VERSION 5.7 ;
  NOWIREEXTENSIONATPIN ON ;
  DIVIDERCHAR "/" ;
  BUSBITCHARS "[]" ;
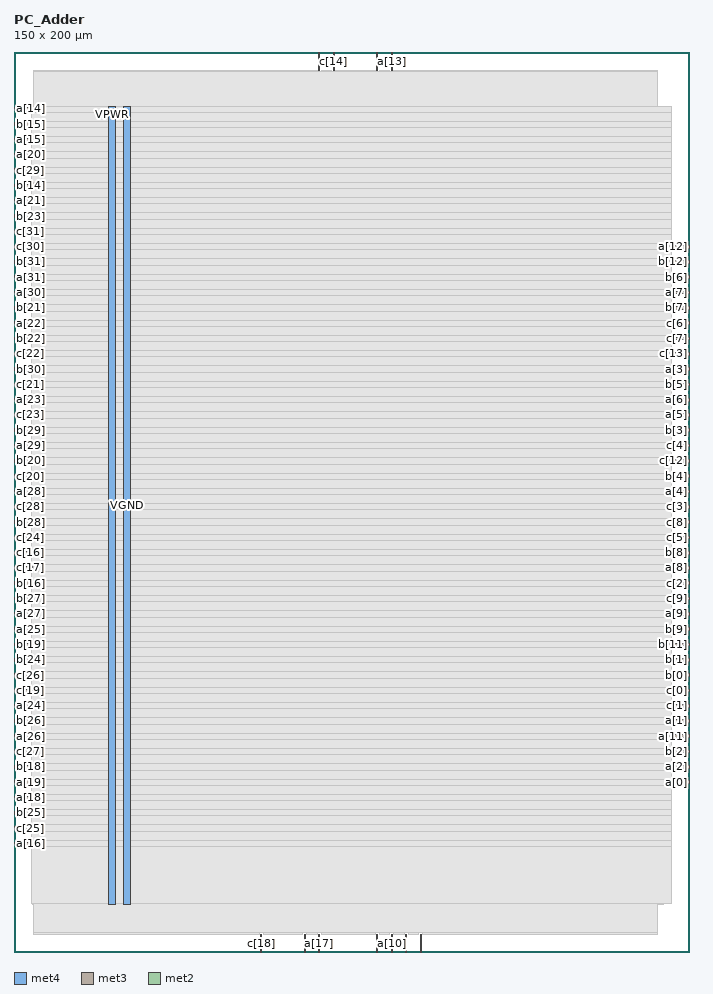
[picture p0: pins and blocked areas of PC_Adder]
MACRO PC_Adder
  CLASS BLOCK ;
  FOREIGN PC_Adder ;
  ORIGIN 0.000 0.000 ;
  SIZE 150.000 BY 200.000 ;
  PIN VGND
    DIRECTION INOUT ;
    USE GROUND ;
    PORT
      LAYER met4 ;
        RECT 24.340 10.640 25.940 187.920 ;
    END
  END VGND
  PIN VPWR
    DIRECTION INOUT ;
    USE POWER ;
    PORT
      LAYER met4 ;
        RECT 21.040 10.640 22.640 187.920 ;
    END
  END VPWR
  PIN a[0]
    DIRECTION INPUT ;
    USE SIGNAL ;
    ANTENNAGATEAREA 0.196500 ;
    PORT
      LAYER met3 ;
        RECT 146.000 37.440 150.000 38.040 ;
    END
  END a[0]
  PIN a[10]
    DIRECTION INPUT ;
    USE SIGNAL ;
    ANTENNAGATEAREA 0.196500 ;
    PORT
      LAYER met2 ;
        RECT 83.810 0.000 84.090 4.000 ;
    END
  END a[10]
  PIN a[11]
    DIRECTION INPUT ;
    USE SIGNAL ;
    ANTENNAGATEAREA 0.196500 ;
    PORT
      LAYER met3 ;
        RECT 146.000 47.640 150.000 48.240 ;
    END
  END a[11]
  PIN a[12]
    DIRECTION INPUT ;
    USE SIGNAL ;
    ANTENNAGATEAREA 0.196500 ;
    PORT
      LAYER met3 ;
        RECT 146.000 156.440 150.000 157.040 ;
    END
  END a[12]
  PIN a[13]
    DIRECTION INPUT ;
    USE SIGNAL ;
    ANTENNAGATEAREA 0.196500 ;
    PORT
      LAYER met2 ;
        RECT 83.810 196.000 84.090 200.000 ;
    END
  END a[13]
  PIN a[14]
    DIRECTION INPUT ;
    USE SIGNAL ;
    ANTENNAGATEAREA 0.196500 ;
    PORT
      LAYER met3 ;
        RECT 0.000 187.040 4.000 187.640 ;
    END
  END a[14]
  PIN a[15]
    DIRECTION INPUT ;
    USE SIGNAL ;
    ANTENNAGATEAREA 0.196500 ;
    PORT
      LAYER met3 ;
        RECT 0.000 180.240 4.000 180.840 ;
    END
  END a[15]
  PIN a[16]
    DIRECTION INPUT ;
    USE SIGNAL ;
    ANTENNAGATEAREA 0.196500 ;
    PORT
      LAYER met3 ;
        RECT 0.000 23.840 4.000 24.440 ;
    END
  END a[16]
  PIN a[17]
    DIRECTION INPUT ;
    USE SIGNAL ;
    ANTENNAGATEAREA 0.196500 ;
    PORT
      LAYER met2 ;
        RECT 67.710 0.000 67.990 4.000 ;
    END
  END a[17]
  PIN a[18]
    DIRECTION INPUT ;
    USE SIGNAL ;
    ANTENNAGATEAREA 0.196500 ;
    PORT
      LAYER met3 ;
        RECT 0.000 34.040 4.000 34.640 ;
    END
  END a[18]
  PIN a[19]
    DIRECTION INPUT ;
    USE SIGNAL ;
    ANTENNAGATEAREA 0.196500 ;
    PORT
      LAYER met3 ;
        RECT 0.000 37.440 4.000 38.040 ;
    END
  END a[19]
  PIN a[1]
    DIRECTION INPUT ;
    USE SIGNAL ;
    ANTENNAGATEAREA 0.196500 ;
    PORT
      LAYER met3 ;
        RECT 146.000 51.040 150.000 51.640 ;
    END
  END a[1]
  PIN a[20]
    DIRECTION INPUT ;
    USE SIGNAL ;
    ANTENNAGATEAREA 0.196500 ;
    PORT
      LAYER met3 ;
        RECT 0.000 176.840 4.000 177.440 ;
    END
  END a[20]
  PIN a[21]
    DIRECTION INPUT ;
    USE SIGNAL ;
    ANTENNAGATEAREA 0.196500 ;
    PORT
      LAYER met3 ;
        RECT 0.000 166.640 4.000 167.240 ;
    END
  END a[21]
  PIN a[22]
    DIRECTION INPUT ;
    USE SIGNAL ;
    ANTENNAGATEAREA 0.196500 ;
    PORT
      LAYER met3 ;
        RECT 0.000 139.440 4.000 140.040 ;
    END
  END a[22]
  PIN a[23]
    DIRECTION INPUT ;
    USE SIGNAL ;
    ANTENNAGATEAREA 0.196500 ;
    PORT
      LAYER met3 ;
        RECT 0.000 122.440 4.000 123.040 ;
    END
  END a[23]
  PIN a[24]
    DIRECTION INPUT ;
    USE SIGNAL ;
    ANTENNAGATEAREA 0.196500 ;
    PORT
      LAYER met3 ;
        RECT 0.000 54.440 4.000 55.040 ;
    END
  END a[24]
  PIN a[25]
    DIRECTION INPUT ;
    USE SIGNAL ;
    ANTENNAGATEAREA 0.196500 ;
    PORT
      LAYER met3 ;
        RECT 0.000 71.440 4.000 72.040 ;
    END
  END a[25]
  PIN a[26]
    DIRECTION INPUT ;
    USE SIGNAL ;
    ANTENNAGATEAREA 0.196500 ;
    PORT
      LAYER met3 ;
        RECT 0.000 47.640 4.000 48.240 ;
    END
  END a[26]
  PIN a[27]
    DIRECTION INPUT ;
    USE SIGNAL ;
    ANTENNAGATEAREA 0.196500 ;
    PORT
      LAYER met3 ;
        RECT 0.000 74.840 4.000 75.440 ;
    END
  END a[27]
  PIN a[28]
    DIRECTION INPUT ;
    USE SIGNAL ;
    ANTENNAGATEAREA 0.196500 ;
    PORT
      LAYER met3 ;
        RECT 0.000 102.040 4.000 102.640 ;
    END
  END a[28]
  PIN a[29]
    DIRECTION INPUT ;
    USE SIGNAL ;
    ANTENNAGATEAREA 0.196500 ;
    PORT
      LAYER met3 ;
        RECT 0.000 112.240 4.000 112.840 ;
    END
  END a[29]
  PIN a[2]
    DIRECTION INPUT ;
    USE SIGNAL ;
    ANTENNAGATEAREA 0.196500 ;
    PORT
      LAYER met3 ;
        RECT 146.000 40.840 150.000 41.440 ;
    END
  END a[2]
  PIN a[30]
    DIRECTION INPUT ;
    USE SIGNAL ;
    ANTENNAGATEAREA 0.196500 ;
    PORT
      LAYER met3 ;
        RECT 0.000 146.240 4.000 146.840 ;
    END
  END a[30]
  PIN a[31]
    DIRECTION INPUT ;
    USE SIGNAL ;
    ANTENNAGATEAREA 0.196500 ;
    PORT
      LAYER met3 ;
        RECT 0.000 149.640 4.000 150.240 ;
    END
  END a[31]
  PIN a[3]
    DIRECTION INPUT ;
    USE SIGNAL ;
    ANTENNAGATEAREA 0.196500 ;
    PORT
      LAYER met3 ;
        RECT 146.000 129.240 150.000 129.840 ;
    END
  END a[3]
  PIN a[4]
    DIRECTION INPUT ;
    USE SIGNAL ;
    ANTENNAGATEAREA 0.196500 ;
    PORT
      LAYER met3 ;
        RECT 146.000 102.040 150.000 102.640 ;
    END
  END a[4]
  PIN a[5]
    DIRECTION INPUT ;
    USE SIGNAL ;
    ANTENNAGATEAREA 0.196500 ;
    PORT
      LAYER met3 ;
        RECT 146.000 119.040 150.000 119.640 ;
    END
  END a[5]
  PIN a[6]
    DIRECTION INPUT ;
    USE SIGNAL ;
    ANTENNAGATEAREA 0.196500 ;
    PORT
      LAYER met3 ;
        RECT 146.000 122.440 150.000 123.040 ;
    END
  END a[6]
  PIN a[7]
    DIRECTION INPUT ;
    USE SIGNAL ;
    ANTENNAGATEAREA 0.196500 ;
    PORT
      LAYER met3 ;
        RECT 146.000 146.240 150.000 146.840 ;
    END
  END a[7]
  PIN a[8]
    DIRECTION INPUT ;
    USE SIGNAL ;
    ANTENNAGATEAREA 0.196500 ;
    PORT
      LAYER met3 ;
        RECT 146.000 85.040 150.000 85.640 ;
    END
  END a[8]
  PIN a[9]
    DIRECTION INPUT ;
    USE SIGNAL ;
    ANTENNAGATEAREA 0.196500 ;
    PORT
      LAYER met3 ;
        RECT 146.000 74.840 150.000 75.440 ;
    END
  END a[9]
  PIN b[0]
    DIRECTION INPUT ;
    USE SIGNAL ;
    ANTENNAGATEAREA 0.196500 ;
    PORT
      LAYER met3 ;
        RECT 146.000 61.240 150.000 61.840 ;
    END
  END b[0]
  PIN b[10]
    DIRECTION INPUT ;
    USE SIGNAL ;
    ANTENNAGATEAREA 0.196500 ;
    PORT
      LAYER met2 ;
        RECT 80.590 0.000 80.870 4.000 ;
    END
  END b[10]
  PIN b[11]
    DIRECTION INPUT ;
    USE SIGNAL ;
    ANTENNAGATEAREA 0.196500 ;
    PORT
      LAYER met3 ;
        RECT 146.000 68.040 150.000 68.640 ;
    END
  END b[11]
  PIN b[12]
    DIRECTION INPUT ;
    USE SIGNAL ;
    ANTENNAGATEAREA 0.196500 ;
    PORT
      LAYER met3 ;
        RECT 146.000 153.040 150.000 153.640 ;
    END
  END b[12]
  PIN b[13]
    DIRECTION INPUT ;
    USE SIGNAL ;
    ANTENNAGATEAREA 0.196500 ;
    PORT
      LAYER met2 ;
        RECT 80.590 196.000 80.870 200.000 ;
    END
  END b[13]
  PIN b[14]
    DIRECTION INPUT ;
    USE SIGNAL ;
    ANTENNAGATEAREA 0.196500 ;
    PORT
      LAYER met3 ;
        RECT 0.000 170.040 4.000 170.640 ;
    END
  END b[14]
  PIN b[15]
    DIRECTION INPUT ;
    USE SIGNAL ;
    ANTENNAGATEAREA 0.196500 ;
    PORT
      LAYER met3 ;
        RECT 0.000 183.640 4.000 184.240 ;
    END
  END b[15]
  PIN b[16]
    DIRECTION INPUT ;
    USE SIGNAL ;
    ANTENNAGATEAREA 0.196500 ;
    PORT
      LAYER met3 ;
        RECT 0.000 81.640 4.000 82.240 ;
    END
  END b[16]
  PIN b[17]
    DIRECTION INPUT ;
    USE SIGNAL ;
    ANTENNAGATEAREA 0.196500 ;
    PORT
      LAYER met2 ;
        RECT 64.490 0.000 64.770 4.000 ;
    END
  END b[17]
  PIN b[18]
    DIRECTION INPUT ;
    USE SIGNAL ;
    ANTENNAGATEAREA 0.196500 ;
    PORT
      LAYER met3 ;
        RECT 0.000 40.840 4.000 41.440 ;
    END
  END b[18]
  PIN b[19]
    DIRECTION INPUT ;
    USE SIGNAL ;
    ANTENNAGATEAREA 0.196500 ;
    PORT
      LAYER met3 ;
        RECT 0.000 68.040 4.000 68.640 ;
    END
  END b[19]
  PIN b[1]
    DIRECTION INPUT ;
    USE SIGNAL ;
    ANTENNAGATEAREA 0.196500 ;
    PORT
      LAYER met3 ;
        RECT 146.000 64.640 150.000 65.240 ;
    END
  END b[1]
  PIN b[20]
    DIRECTION INPUT ;
    USE SIGNAL ;
    ANTENNAGATEAREA 0.196500 ;
    PORT
      LAYER met3 ;
        RECT 0.000 108.840 4.000 109.440 ;
    END
  END b[20]
  PIN b[21]
    DIRECTION INPUT ;
    USE SIGNAL ;
    ANTENNAGATEAREA 0.196500 ;
    PORT
      LAYER met3 ;
        RECT 0.000 142.840 4.000 143.440 ;
    END
  END b[21]
  PIN b[22]
    DIRECTION INPUT ;
    USE SIGNAL ;
    ANTENNAGATEAREA 0.196500 ;
    PORT
      LAYER met3 ;
        RECT 0.000 136.040 4.000 136.640 ;
    END
  END b[22]
  PIN b[23]
    DIRECTION INPUT ;
    USE SIGNAL ;
    ANTENNAGATEAREA 0.196500 ;
    PORT
      LAYER met3 ;
        RECT 0.000 163.240 4.000 163.840 ;
    END
  END b[23]
  PIN b[24]
    DIRECTION INPUT ;
    USE SIGNAL ;
    ANTENNAGATEAREA 0.196500 ;
    PORT
      LAYER met3 ;
        RECT 0.000 64.640 4.000 65.240 ;
    END
  END b[24]
  PIN b[25]
    DIRECTION INPUT ;
    USE SIGNAL ;
    ANTENNAGATEAREA 0.196500 ;
    PORT
      LAYER met3 ;
        RECT 0.000 30.640 4.000 31.240 ;
    END
  END b[25]
  PIN b[26]
    DIRECTION INPUT ;
    USE SIGNAL ;
    ANTENNAGATEAREA 0.196500 ;
    PORT
      LAYER met3 ;
        RECT 0.000 51.040 4.000 51.640 ;
    END
  END b[26]
  PIN b[27]
    DIRECTION INPUT ;
    USE SIGNAL ;
    ANTENNAGATEAREA 0.196500 ;
    PORT
      LAYER met3 ;
        RECT 0.000 78.240 4.000 78.840 ;
    END
  END b[27]
  PIN b[28]
    DIRECTION INPUT ;
    USE SIGNAL ;
    ANTENNAGATEAREA 0.196500 ;
    PORT
      LAYER met3 ;
        RECT 0.000 95.240 4.000 95.840 ;
    END
  END b[28]
  PIN b[29]
    DIRECTION INPUT ;
    USE SIGNAL ;
    ANTENNAGATEAREA 0.196500 ;
    PORT
      LAYER met3 ;
        RECT 0.000 115.640 4.000 116.240 ;
    END
  END b[29]
  PIN b[2]
    DIRECTION INPUT ;
    USE SIGNAL ;
    ANTENNAGATEAREA 0.196500 ;
    PORT
      LAYER met3 ;
        RECT 146.000 44.240 150.000 44.840 ;
    END
  END b[2]
  PIN b[30]
    DIRECTION INPUT ;
    USE SIGNAL ;
    ANTENNAGATEAREA 0.196500 ;
    PORT
      LAYER met3 ;
        RECT 0.000 129.240 4.000 129.840 ;
    END
  END b[30]
  PIN b[31]
    DIRECTION INPUT ;
    USE SIGNAL ;
    ANTENNAGATEAREA 0.196500 ;
    PORT
      LAYER met3 ;
        RECT 0.000 153.040 4.000 153.640 ;
    END
  END b[31]
  PIN b[3]
    DIRECTION INPUT ;
    USE SIGNAL ;
    ANTENNAGATEAREA 0.196500 ;
    PORT
      LAYER met3 ;
        RECT 146.000 115.640 150.000 116.240 ;
    END
  END b[3]
  PIN b[4]
    DIRECTION INPUT ;
    USE SIGNAL ;
    ANTENNAGATEAREA 0.196500 ;
    PORT
      LAYER met3 ;
        RECT 146.000 105.440 150.000 106.040 ;
    END
  END b[4]
  PIN b[5]
    DIRECTION INPUT ;
    USE SIGNAL ;
    ANTENNAGATEAREA 0.196500 ;
    PORT
      LAYER met3 ;
        RECT 146.000 125.840 150.000 126.440 ;
    END
  END b[5]
  PIN b[6]
    DIRECTION INPUT ;
    USE SIGNAL ;
    ANTENNAGATEAREA 0.196500 ;
    PORT
      LAYER met3 ;
        RECT 146.000 149.640 150.000 150.240 ;
    END
  END b[6]
  PIN b[7]
    DIRECTION INPUT ;
    USE SIGNAL ;
    ANTENNAGATEAREA 0.196500 ;
    PORT
      LAYER met3 ;
        RECT 146.000 142.840 150.000 143.440 ;
    END
  END b[7]
  PIN b[8]
    DIRECTION INPUT ;
    USE SIGNAL ;
    ANTENNAGATEAREA 0.196500 ;
    PORT
      LAYER met3 ;
        RECT 146.000 88.440 150.000 89.040 ;
    END
  END b[8]
  PIN b[9]
    DIRECTION INPUT ;
    USE SIGNAL ;
    ANTENNAGATEAREA 0.196500 ;
    PORT
      LAYER met3 ;
        RECT 146.000 71.440 150.000 72.040 ;
    END
  END b[9]
  PIN c[0]
    DIRECTION OUTPUT ;
    USE SIGNAL ;
    ANTENNADIFFAREA 0.445500 ;
    PORT
      LAYER met3 ;
        RECT 146.000 57.840 150.000 58.440 ;
    END
  END c[0]
  PIN c[10]
    DIRECTION OUTPUT ;
    USE SIGNAL ;
    ANTENNADIFFAREA 0.445500 ;
    PORT
      LAYER met2 ;
        RECT 90.250 0.000 90.530 4.000 ;
    END
  END c[10]
  PIN c[11]
    DIRECTION OUTPUT ;
    USE SIGNAL ;
    ANTENNADIFFAREA 0.445500 ;
    PORT
      LAYER met2 ;
        RECT 87.030 0.000 87.310 4.000 ;
    END
  END c[11]
  PIN c[12]
    DIRECTION OUTPUT ;
    USE SIGNAL ;
    ANTENNADIFFAREA 0.445500 ;
    PORT
      LAYER met3 ;
        RECT 146.000 108.840 150.000 109.440 ;
    END
  END c[12]
  PIN c[13]
    DIRECTION OUTPUT ;
    USE SIGNAL ;
    ANTENNADIFFAREA 0.445500 ;
    PORT
      LAYER met3 ;
        RECT 146.000 132.640 150.000 133.240 ;
    END
  END c[13]
  PIN c[14]
    DIRECTION OUTPUT ;
    USE SIGNAL ;
    ANTENNADIFFAREA 0.795200 ;
    PORT
      LAYER met2 ;
        RECT 70.930 196.000 71.210 200.000 ;
    END
  END c[14]
  PIN c[15]
    DIRECTION OUTPUT ;
    USE SIGNAL ;
    ANTENNADIFFAREA 0.795200 ;
    PORT
      LAYER met2 ;
        RECT 67.710 196.000 67.990 200.000 ;
    END
  END c[15]
  PIN c[16]
    DIRECTION OUTPUT ;
    USE SIGNAL ;
    ANTENNADIFFAREA 0.445500 ;
    PORT
      LAYER met3 ;
        RECT 0.000 88.440 4.000 89.040 ;
    END
  END c[16]
  PIN c[17]
    DIRECTION OUTPUT ;
    USE SIGNAL ;
    ANTENNADIFFAREA 0.445500 ;
    PORT
      LAYER met3 ;
        RECT 0.000 85.040 4.000 85.640 ;
    END
  END c[17]
  PIN c[18]
    DIRECTION OUTPUT ;
    USE SIGNAL ;
    ANTENNADIFFAREA 0.445500 ;
    PORT
      LAYER met2 ;
        RECT 54.830 0.000 55.110 4.000 ;
    END
  END c[18]
  PIN c[19]
    DIRECTION OUTPUT ;
    USE SIGNAL ;
    ANTENNADIFFAREA 0.445500 ;
    PORT
      LAYER met3 ;
        RECT 0.000 57.840 4.000 58.440 ;
    END
  END c[19]
  PIN c[1]
    DIRECTION OUTPUT ;
    USE SIGNAL ;
    ANTENNADIFFAREA 0.445500 ;
    PORT
      LAYER met3 ;
        RECT 146.000 54.440 150.000 55.040 ;
    END
  END c[1]
  PIN c[20]
    DIRECTION OUTPUT ;
    USE SIGNAL ;
    ANTENNADIFFAREA 0.445500 ;
    PORT
      LAYER met3 ;
        RECT 0.000 105.440 4.000 106.040 ;
    END
  END c[20]
  PIN c[21]
    DIRECTION OUTPUT ;
    USE SIGNAL ;
    ANTENNADIFFAREA 0.445500 ;
    PORT
      LAYER met3 ;
        RECT 0.000 125.840 4.000 126.440 ;
    END
  END c[21]
  PIN c[22]
    DIRECTION OUTPUT ;
    USE SIGNAL ;
    ANTENNADIFFAREA 0.445500 ;
    PORT
      LAYER met3 ;
        RECT 0.000 132.640 4.000 133.240 ;
    END
  END c[22]
  PIN c[23]
    DIRECTION OUTPUT ;
    USE SIGNAL ;
    ANTENNADIFFAREA 0.445500 ;
    PORT
      LAYER met3 ;
        RECT 0.000 119.040 4.000 119.640 ;
    END
  END c[23]
  PIN c[24]
    DIRECTION OUTPUT ;
    USE SIGNAL ;
    ANTENNADIFFAREA 0.445500 ;
    PORT
      LAYER met3 ;
        RECT 0.000 91.840 4.000 92.440 ;
    END
  END c[24]
  PIN c[25]
    DIRECTION OUTPUT ;
    USE SIGNAL ;
    ANTENNADIFFAREA 0.445500 ;
    PORT
      LAYER met3 ;
        RECT 0.000 27.240 4.000 27.840 ;
    END
  END c[25]
  PIN c[26]
    DIRECTION OUTPUT ;
    USE SIGNAL ;
    ANTENNADIFFAREA 0.445500 ;
    PORT
      LAYER met3 ;
        RECT 0.000 61.240 4.000 61.840 ;
    END
  END c[26]
  PIN c[27]
    DIRECTION OUTPUT ;
    USE SIGNAL ;
    ANTENNADIFFAREA 0.445500 ;
    PORT
      LAYER met3 ;
        RECT 0.000 44.240 4.000 44.840 ;
    END
  END c[27]
  PIN c[28]
    DIRECTION OUTPUT ;
    USE SIGNAL ;
    ANTENNADIFFAREA 0.445500 ;
    PORT
      LAYER met3 ;
        RECT 0.000 98.640 4.000 99.240 ;
    END
  END c[28]
  PIN c[29]
    DIRECTION OUTPUT ;
    USE SIGNAL ;
    ANTENNADIFFAREA 0.445500 ;
    PORT
      LAYER met3 ;
        RECT 0.000 173.440 4.000 174.040 ;
    END
  END c[29]
  PIN c[2]
    DIRECTION OUTPUT ;
    USE SIGNAL ;
    ANTENNADIFFAREA 0.445500 ;
    PORT
      LAYER met3 ;
        RECT 146.000 81.640 150.000 82.240 ;
    END
  END c[2]
  PIN c[30]
    DIRECTION OUTPUT ;
    USE SIGNAL ;
    ANTENNADIFFAREA 0.445500 ;
    PORT
      LAYER met3 ;
        RECT 0.000 156.440 4.000 157.040 ;
    END
  END c[30]
  PIN c[31]
    DIRECTION OUTPUT ;
    USE SIGNAL ;
    ANTENNADIFFAREA 0.445500 ;
    PORT
      LAYER met3 ;
        RECT 0.000 159.840 4.000 160.440 ;
    END
  END c[31]
  PIN c[3]
    DIRECTION OUTPUT ;
    USE SIGNAL ;
    ANTENNADIFFAREA 0.445500 ;
    PORT
      LAYER met3 ;
        RECT 146.000 98.640 150.000 99.240 ;
    END
  END c[3]
  PIN c[4]
    DIRECTION OUTPUT ;
    USE SIGNAL ;
    ANTENNADIFFAREA 0.445500 ;
    PORT
      LAYER met3 ;
        RECT 146.000 112.240 150.000 112.840 ;
    END
  END c[4]
  PIN c[5]
    DIRECTION OUTPUT ;
    USE SIGNAL ;
    ANTENNADIFFAREA 0.445500 ;
    PORT
      LAYER met3 ;
        RECT 146.000 91.840 150.000 92.440 ;
    END
  END c[5]
  PIN c[6]
    DIRECTION OUTPUT ;
    USE SIGNAL ;
    ANTENNADIFFAREA 0.445500 ;
    PORT
      LAYER met3 ;
        RECT 146.000 139.440 150.000 140.040 ;
    END
  END c[6]
  PIN c[7]
    DIRECTION OUTPUT ;
    USE SIGNAL ;
    ANTENNADIFFAREA 0.445500 ;
    PORT
      LAYER met3 ;
        RECT 146.000 136.040 150.000 136.640 ;
    END
  END c[7]
  PIN c[8]
    DIRECTION OUTPUT ;
    USE SIGNAL ;
    ANTENNADIFFAREA 0.445500 ;
    PORT
      LAYER met3 ;
        RECT 146.000 95.240 150.000 95.840 ;
    END
  END c[8]
  PIN c[9]
    DIRECTION OUTPUT ;
    USE SIGNAL ;
    ANTENNADIFFAREA 0.445500 ;
    PORT
      LAYER met3 ;
        RECT 146.000 78.240 150.000 78.840 ;
    END
  END c[9]
  OBS
      LAYER nwell ;
        RECT 5.330 10.795 144.630 187.870 ;
      LAYER li1 ;
        RECT 5.520 10.795 144.440 187.765 ;
      LAYER met1 ;
        RECT 4.210 10.640 144.440 187.920 ;
      LAYER met2 ;
        RECT 4.230 195.720 67.430 196.000 ;
        RECT 68.270 195.720 70.650 196.000 ;
        RECT 71.490 195.720 80.310 196.000 ;
        RECT 81.150 195.720 83.530 196.000 ;
        RECT 84.370 195.720 142.970 196.000 ;
        RECT 4.230 4.280 142.970 195.720 ;
        RECT 4.230 4.000 54.550 4.280 ;
        RECT 55.390 4.000 64.210 4.280 ;
        RECT 65.050 4.000 67.430 4.280 ;
        RECT 68.270 4.000 80.310 4.280 ;
        RECT 81.150 4.000 83.530 4.280 ;
        RECT 84.370 4.000 86.750 4.280 ;
        RECT 87.590 4.000 89.970 4.280 ;
        RECT 90.810 4.000 142.970 4.280 ;
      LAYER met3 ;
        RECT 4.400 186.640 146.000 187.845 ;
        RECT 3.990 184.640 146.000 186.640 ;
        RECT 4.400 183.240 146.000 184.640 ;
        RECT 3.990 181.240 146.000 183.240 ;
        RECT 4.400 179.840 146.000 181.240 ;
        RECT 3.990 177.840 146.000 179.840 ;
        RECT 4.400 176.440 146.000 177.840 ;
        RECT 3.990 174.440 146.000 176.440 ;
        RECT 4.400 173.040 146.000 174.440 ;
        RECT 3.990 171.040 146.000 173.040 ;
        RECT 4.400 169.640 146.000 171.040 ;
        RECT 3.990 167.640 146.000 169.640 ;
        RECT 4.400 166.240 146.000 167.640 ;
        RECT 3.990 164.240 146.000 166.240 ;
        RECT 4.400 162.840 146.000 164.240 ;
        RECT 3.990 160.840 146.000 162.840 ;
        RECT 4.400 159.440 146.000 160.840 ;
        RECT 3.990 157.440 146.000 159.440 ;
        RECT 4.400 156.040 145.600 157.440 ;
        RECT 3.990 154.040 146.000 156.040 ;
        RECT 4.400 152.640 145.600 154.040 ;
        RECT 3.990 150.640 146.000 152.640 ;
        RECT 4.400 149.240 145.600 150.640 ;
        RECT 3.990 147.240 146.000 149.240 ;
        RECT 4.400 145.840 145.600 147.240 ;
        RECT 3.990 143.840 146.000 145.840 ;
        RECT 4.400 142.440 145.600 143.840 ;
        RECT 3.990 140.440 146.000 142.440 ;
        RECT 4.400 139.040 145.600 140.440 ;
        RECT 3.990 137.040 146.000 139.040 ;
        RECT 4.400 135.640 145.600 137.040 ;
        RECT 3.990 133.640 146.000 135.640 ;
        RECT 4.400 132.240 145.600 133.640 ;
        RECT 3.990 130.240 146.000 132.240 ;
        RECT 4.400 128.840 145.600 130.240 ;
        RECT 3.990 126.840 146.000 128.840 ;
        RECT 4.400 125.440 145.600 126.840 ;
        RECT 3.990 123.440 146.000 125.440 ;
        RECT 4.400 122.040 145.600 123.440 ;
        RECT 3.990 120.040 146.000 122.040 ;
        RECT 4.400 118.640 145.600 120.040 ;
        RECT 3.990 116.640 146.000 118.640 ;
        RECT 4.400 115.240 145.600 116.640 ;
        RECT 3.990 113.240 146.000 115.240 ;
        RECT 4.400 111.840 145.600 113.240 ;
        RECT 3.990 109.840 146.000 111.840 ;
        RECT 4.400 108.440 145.600 109.840 ;
        RECT 3.990 106.440 146.000 108.440 ;
        RECT 4.400 105.040 145.600 106.440 ;
        RECT 3.990 103.040 146.000 105.040 ;
        RECT 4.400 101.640 145.600 103.040 ;
        RECT 3.990 99.640 146.000 101.640 ;
        RECT 4.400 98.240 145.600 99.640 ;
        RECT 3.990 96.240 146.000 98.240 ;
        RECT 4.400 94.840 145.600 96.240 ;
        RECT 3.990 92.840 146.000 94.840 ;
        RECT 4.400 91.440 145.600 92.840 ;
        RECT 3.990 89.440 146.000 91.440 ;
        RECT 4.400 88.040 145.600 89.440 ;
        RECT 3.990 86.040 146.000 88.040 ;
        RECT 4.400 84.640 145.600 86.040 ;
        RECT 3.990 82.640 146.000 84.640 ;
        RECT 4.400 81.240 145.600 82.640 ;
        RECT 3.990 79.240 146.000 81.240 ;
        RECT 4.400 77.840 145.600 79.240 ;
        RECT 3.990 75.840 146.000 77.840 ;
        RECT 4.400 74.440 145.600 75.840 ;
        RECT 3.990 72.440 146.000 74.440 ;
        RECT 4.400 71.040 145.600 72.440 ;
        RECT 3.990 69.040 146.000 71.040 ;
        RECT 4.400 67.640 145.600 69.040 ;
        RECT 3.990 65.640 146.000 67.640 ;
        RECT 4.400 64.240 145.600 65.640 ;
        RECT 3.990 62.240 146.000 64.240 ;
        RECT 4.400 60.840 145.600 62.240 ;
        RECT 3.990 58.840 146.000 60.840 ;
        RECT 4.400 57.440 145.600 58.840 ;
        RECT 3.990 55.440 146.000 57.440 ;
        RECT 4.400 54.040 145.600 55.440 ;
        RECT 3.990 52.040 146.000 54.040 ;
        RECT 4.400 50.640 145.600 52.040 ;
        RECT 3.990 48.640 146.000 50.640 ;
        RECT 4.400 47.240 145.600 48.640 ;
        RECT 3.990 45.240 146.000 47.240 ;
        RECT 4.400 43.840 145.600 45.240 ;
        RECT 3.990 41.840 146.000 43.840 ;
        RECT 4.400 40.440 145.600 41.840 ;
        RECT 3.990 38.440 146.000 40.440 ;
        RECT 4.400 37.040 145.600 38.440 ;
        RECT 3.990 35.040 146.000 37.040 ;
        RECT 4.400 33.640 146.000 35.040 ;
        RECT 3.990 31.640 146.000 33.640 ;
        RECT 4.400 30.240 146.000 31.640 ;
        RECT 3.990 28.240 146.000 30.240 ;
        RECT 4.400 26.840 146.000 28.240 ;
        RECT 3.990 24.840 146.000 26.840 ;
        RECT 4.400 23.440 146.000 24.840 ;
        RECT 3.990 10.715 146.000 23.440 ;
  END
END PC_Adder
END LIBRARY

